VERSION 5.7 ;
BUSBITCHARS "[]" ;
DIVIDERCHAR "/" ;

PROPERTYDEFINITIONS
  LAYER LEF58_TYPE STRING ;
  LAYER LEF58_ENCLOSURE STRING ;
  LAYER LEF58_SPACING STRING ;
  LAYER LEF58_WIDTH STRING ;
END PROPERTYDEFINITIONS

UNITS
  TIME NANOSECONDS 1 ;
  CAPACITANCE PICOFARADS 1 ;
  RESISTANCE OHMS 1 ;
  DATABASE MICRONS 1000 ;
END UNITS
MANUFACTURINGGRID 0.005 ;
LAYER OverlapCheck
  TYPE OVERLAP ;
END OverlapCheck

LAYER WN
  TYPE MASTERSLICE ;
  PROPERTY LEF58_TYPE "TYPE NWELL ;" ;
  PROPERTY LEF58_SPACING "SPACING 2.8 ;" ;
  PROPERTY LEF58_WIDTH "WIDTH 0.86 ;" ;
END WN

LAYER ACTIVE
  TYPE MASTERSLICE ;
  PROPERTY LEF58_TYPE "TYPE DIFFUSION ;" ;
END ACTIVE

LAYER XP
  TYPE IMPLANT ;
  WIDTH 0.44 ;
  SPACING 0.44 ;
END XP

LAYER XN
  TYPE IMPLANT ;
  WIDTH 0.44 ;
  SPACING 0.44 ;
END XN

LAYER GC
  TYPE MASTERSLICE ;
END GC

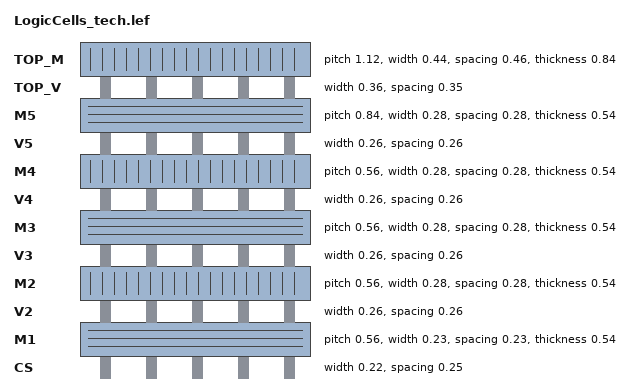
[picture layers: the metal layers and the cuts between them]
LAYER CS
  TYPE CUT ;
  SPACING 0.25 ;
  WIDTH 0.22 ;
  ENCLOSURE BELOW 0.1 0.1 ;
  ENCLOSURE ABOVE 0.06 0.005 ;
  ANTENNAMODEL OXIDE1 ;
END CS

LAYER M1
  TYPE ROUTING ;
  DIRECTION HORIZONTAL ;
  PITCH 0.56 0.56 ;
  WIDTH 0.23 ;
  OFFSET 0.28 ;
  AREA 0.202 ;
  SPACING 0.23 ;
  SPACING 0.6 RANGE 10 10000 ;
  SPACING 0.23 SAMENET ;
  RESISTANCE RPERSQ 0.08 ;
  CAPACITANCE CPERSQDIST 3.51e-05 ;
  HEIGHT 1.05 ;
  THICKNESS 0.54 ;
  ANTENNAMODEL OXIDE1 ;
    ANTENNASIDEAREARATIO 400 ;
    ANTENNADIFFSIDEAREARATIO PWL ( ( 0 400 ) ( 0.203 400 ) ( 0.203001 2281.2 ) ( 1.203 2681.2 ) ) ;
END M1

LAYER V2
  TYPE CUT ;
  SPACING 0.26 ;
  SPACING 0 LAYER CS ;
  WIDTH 0.26 ;
  ENCLOSURE BELOW 0.06 0.01 ;
  ENCLOSURE ABOVE 0.06 0.01 ;
  ANTENNAMODEL OXIDE1 ;
    ANTENNAAREARATIO 20 ;
    ANTENNADIFFAREARATIO PWL ( ( 0 20 ) ( 0.203 20 ) ( 0.203001 91.9161 ) ( 1.203 175.246 ) ) ;
END V2

LAYER M2
  TYPE ROUTING ;
  DIRECTION VERTICAL ;
  PITCH 0.56 0.56 ;
  WIDTH 0.28 ;
  OFFSET 0.28 ;
  AREA 0.202 ;
  SPACING 0.28 ;
  SPACING 0.6 RANGE 10 10000 ;
  SPACING 0.28 SAMENET ;
  RESISTANCE RPERSQ 0.08 ;
  CAPACITANCE CPERSQDIST 1.46e-05 ;
  HEIGHT 2.41 ;
  THICKNESS 0.54 ;
  ANTENNAMODEL OXIDE1 ;
    ANTENNASIDEAREARATIO 400 ;
    ANTENNADIFFSIDEAREARATIO PWL ( ( 0 400 ) ( 0.203 400 ) ( 0.203001 2281.2 ) ( 1.203 2681.2 ) ) ;
END M2

LAYER V3
  TYPE CUT ;
  SPACING 0.26 ;
  SPACING 0 SAMENET LAYER V2 STACK ;
  WIDTH 0.26 ;
  ENCLOSURE BELOW 0.06 0.01 ;
  ENCLOSURE ABOVE 0.06 0.01 ;
  ANTENNAMODEL OXIDE1 ;
    ANTENNAAREARATIO 20 ;
    ANTENNADIFFAREARATIO PWL ( ( 0 20 ) ( 0.203 20 ) ( 0.203001 91.9161 ) ( 1.203 175.246 ) ) ;
END V3

LAYER M3
  TYPE ROUTING ;
  DIRECTION HORIZONTAL ;
  PITCH 0.56 0.56 ;
  WIDTH 0.28 ;
  OFFSET 0.28 ;
  AREA 0.202 ;
  SPACING 0.28 ;
  SPACING 0.6 RANGE 10 10000 ;
  SPACING 0.28 SAMENET ;
  RESISTANCE RPERSQ 0.08 ;
  CAPACITANCE CPERSQDIST 9.24e-06 ;
  HEIGHT 3.77 ;
  THICKNESS 0.54 ;
  ANTENNAMODEL OXIDE1 ;
    ANTENNASIDEAREARATIO 400 ;
    ANTENNADIFFSIDEAREARATIO PWL ( ( 0 400 ) ( 0.203 400 ) ( 0.203001 2281.2 ) ( 1.203 2681.2 ) ) ;
END M3

LAYER V4
  TYPE CUT ;
  SPACING 0.26 ;
  SPACING 0 SAMENET LAYER V3 STACK ;
  WIDTH 0.26 ;
  ENCLOSURE BELOW 0.06 0.01 ;
  ENCLOSURE ABOVE 0.06 0.01 ;
  ANTENNAMODEL OXIDE1 ;
    ANTENNAAREARATIO 20 ;
    ANTENNADIFFAREARATIO PWL ( ( 0 20 ) ( 0.203 20 ) ( 0.203001 91.9161 ) ( 1.203 175.246 ) ) ;
END V4

LAYER M4
  TYPE ROUTING ;
  DIRECTION VERTICAL ;
  PITCH 0.56 0.56 ;
  WIDTH 0.28 ;
  OFFSET 0.28 ;
  AREA 0.202 ;
  SPACING 0.28 ;
  SPACING 0.6 RANGE 10 10000 ;
  SPACING 0.28 SAMENET ;
  RESISTANCE RPERSQ 0.08 ;
  CAPACITANCE CPERSQDIST 6.75e-06 ;
  HEIGHT 5.13 ;
  THICKNESS 0.54 ;
  ANTENNAMODEL OXIDE1 ;
    ANTENNASIDEAREARATIO 400 ;
    ANTENNADIFFSIDEAREARATIO PWL ( ( 0 400 ) ( 0.203 400 ) ( 0.203001 2281.2 ) ( 1.203 2681.2 ) ) ;
END M4

LAYER V5
  TYPE CUT ;
  SPACING 0.26 ;
  SPACING 0 SAMENET LAYER V4 STACK ;
  WIDTH 0.26 ;
  ENCLOSURE BELOW 0.06 0.01 ;
  ENCLOSURE ABOVE 0.06 0.01 ;
  ANTENNAMODEL OXIDE1 ;
    ANTENNAAREARATIO 20 ;
    ANTENNADIFFAREARATIO PWL ( ( 0 20 ) ( 0.203 20 ) ( 0.203001 91.9161 ) ( 1.203 175.246 ) ) ;
END V5

LAYER M5
  TYPE ROUTING ;
  DIRECTION HORIZONTAL ;
  PITCH 0.84 0.84 ;
  WIDTH 0.28 ;
  OFFSET 0.42 ;
  AREA 0.202 ;
  SPACING 0.28 ;
  SPACING 0.6 RANGE 10 10000 ;
  SPACING 0.28 SAMENET ;
  RESISTANCE RPERSQ 0.08 ;
  CAPACITANCE CPERSQDIST 5.32e-06 ;
  HEIGHT 6.49 ;
  THICKNESS 0.54 ;
  ANTENNAMODEL OXIDE1 ;
    ANTENNASIDEAREARATIO 400 ;
    ANTENNADIFFSIDEAREARATIO PWL ( ( 0 400 ) ( 0.203 400 ) ( 0.203001 2281.2 ) ( 1.203 2681.2 ) ) ;
END M5

LAYER TOP_V
  TYPE CUT ;
  SPACING 0.35 ;
  SPACING 0 SAMENET LAYER V5 STACK ;
  WIDTH 0.36 ;
  ENCLOSURE BELOW 0.06 0.01 ;
  ENCLOSURE ABOVE 0.09 0.09 ;
  ANTENNAMODEL OXIDE1 ;
    ANTENNAAREARATIO 20 ;
    ANTENNADIFFAREARATIO PWL ( ( 0 20 ) ( 0.203 20 ) ( 0.203001 91.9161 ) ( 1.203 175.246 ) ) ;
END TOP_V

LAYER TOP_M
  TYPE ROUTING ;
  DIRECTION VERTICAL ;
  PITCH 1.12 1.12 ;
  WIDTH 0.44 ;
  OFFSET 0.56 ;
  AREA 0.562 ;
  SPACING 0.46 ;
  SPACING 0.6 RANGE 10 10000 ;
  SPACING 0.46 SAMENET ;
  RESISTANCE RPERSQ 0.04 ;
  CAPACITANCE CPERSQDIST 4.389e-06 ;
  HEIGHT 7.83 ;
  THICKNESS 0.84 ;
  ANTENNAMODEL OXIDE1 ;
    ANTENNASIDEAREARATIO 400 ;
    ANTENNADIFFSIDEAREARATIO PWL ( ( 0 400 ) ( 0.203 400 ) ( 0.203001 31624 ) ( 1.203 39624 ) ) ;
END TOP_M

VIARULE ML_M5_LD GENERATE
  LAYER M5 ;
    ENCLOSURE 0.1 0.1 ;
  LAYER TOP_M ;
    ENCLOSURE 0.1 0.1 ;
  LAYER TOP_V ;
    RECT -0.18 -0.18 0.18 0.18 ;
    SPACING 0.71 BY 0.71 ;
END ML_M5_LD

VIARULE M5_M4_LD GENERATE
  LAYER M4 ;
    ENCLOSURE 0.1 0.1 ;
  LAYER M5 ;
    ENCLOSURE 0.1 0.1 ;
  LAYER V5 ;
    RECT -0.13 -0.13 0.13 0.13 ;
    SPACING 0.52 BY 0.52 ;
END M5_M4_LD

VIARULE M4_M3_LD GENERATE
  LAYER M3 ;
    ENCLOSURE 0.1 0.1 ;
  LAYER M4 ;
    ENCLOSURE 0.1 0.1 ;
  LAYER V4 ;
    RECT -0.13 -0.13 0.13 0.13 ;
    SPACING 0.52 BY 0.52 ;
END M4_M3_LD

VIARULE M3_M2_LD GENERATE
  LAYER M2 ;
    ENCLOSURE 0.1 0.1 ;
  LAYER M3 ;
    ENCLOSURE 0.1 0.1 ;
  LAYER V3 ;
    RECT -0.13 -0.13 0.13 0.13 ;
    SPACING 0.52 BY 0.52 ;
END M3_M2_LD

VIARULE M2_M1_LD GENERATE
  LAYER M1 ;
    ENCLOSURE 0.1 0.1 ;
  LAYER M2 ;
    ENCLOSURE 0.1 0.1 ;
  LAYER V2 ;
    RECT -0.13 -0.13 0.13 0.13 ;
    SPACING 0.52 BY 0.52 ;
END M2_M1_LD

VIARULE ML_M5_S GENERATE DEFAULT
  LAYER M5 ;
    ENCLOSURE 0.01 0.01 ;
  LAYER TOP_M ;
    ENCLOSURE 0.09 0.09 ;
  LAYER TOP_V ;
    RECT -0.18 -0.18 0.18 0.18 ;
    SPACING 0.71 BY 0.71 ;
END ML_M5_S

VIARULE M5_M4_S GENERATE DEFAULT
  LAYER M4 ;
    ENCLOSURE 0.01 0.01 ;
  LAYER M5 ;
    ENCLOSURE 0.01 0.01 ;
  LAYER V5 ;
    RECT -0.13 -0.13 0.13 0.13 ;
    SPACING 0.52 BY 0.52 ;
END M5_M4_S

VIARULE M4_M3_S GENERATE DEFAULT
  LAYER M3 ;
    ENCLOSURE 0.01 0.01 ;
  LAYER M4 ;
    ENCLOSURE 0.01 0.01 ;
  LAYER V4 ;
    RECT -0.13 -0.13 0.13 0.13 ;
    SPACING 0.52 BY 0.52 ;
END M4_M3_S

VIARULE M3_M2_S GENERATE DEFAULT
  LAYER M2 ;
    ENCLOSURE 0.01 0.01 ;
  LAYER M3 ;
    ENCLOSURE 0.01 0.01 ;
  LAYER V3 ;
    RECT -0.13 -0.13 0.13 0.13 ;
    SPACING 0.52 BY 0.52 ;
END M3_M2_S

VIARULE M2_M1_S GENERATE DEFAULT
  LAYER M1 ;
    ENCLOSURE 0.01 0.01 ;
  LAYER M2 ;
    ENCLOSURE 0.01 0.01 ;
  LAYER V2 ;
    RECT -0.13 -0.13 0.13 0.13 ;
    SPACING 0.52 BY 0.52 ;
END M2_M1_S

VIARULE ML_M5 GENERATE
  LAYER M5 ;
    ENCLOSURE 0.06 0.06 ;
  LAYER TOP_M ;
    ENCLOSURE 0.09 0.09 ;
  LAYER TOP_V ;
    RECT -0.18 -0.18 0.18 0.18 ;
    SPACING 0.71 BY 0.71 ;
END ML_M5

VIARULE M5_M4 GENERATE
  LAYER M4 ;
    ENCLOSURE 0.06 0.06 ;
  LAYER M5 ;
    ENCLOSURE 0.06 0.06 ;
  LAYER V5 ;
    RECT -0.13 -0.13 0.13 0.13 ;
    SPACING 0.52 BY 0.52 ;
END M5_M4

VIARULE M4_M3 GENERATE
  LAYER M3 ;
    ENCLOSURE 0.06 0.06 ;
  LAYER M4 ;
    ENCLOSURE 0.06 0.06 ;
  LAYER V4 ;
    RECT -0.13 -0.13 0.13 0.13 ;
    SPACING 0.52 BY 0.52 ;
END M4_M3

VIARULE M3_M2 GENERATE
  LAYER M2 ;
    ENCLOSURE 0.06 0.06 ;
  LAYER M3 ;
    ENCLOSURE 0.06 0.06 ;
  LAYER V3 ;
    RECT -0.13 -0.13 0.13 0.13 ;
    SPACING 0.52 BY 0.52 ;
END M3_M2

VIARULE M2_M1 GENERATE
  LAYER M1 ;
    ENCLOSURE 0.06 0.06 ;
  LAYER M2 ;
    ENCLOSURE 0.06 0.06 ;
  LAYER V2 ;
    RECT -0.13 -0.13 0.13 0.13 ;
    SPACING 0.52 BY 0.52 ;
END M2_M1

VIARULE M1_PO_4X GENERATE
  LAYER GC ;
    ENCLOSURE 0.1 0.1 ;
  LAYER M1 ;
    ENCLOSURE 0.06 0.06 ;
  LAYER CS ;
    RECT -0.11 -0.11 0.11 0.11 ;
    SPACING 0.5 BY 0.5 ;
END M1_PO_4X

VIARULE M1_PO GENERATE
  LAYER GC ;
    ENCLOSURE 0.1 0.1 ;
  LAYER M1 ;
    ENCLOSURE 0.06 0.06 ;
  LAYER CS ;
    RECT -0.11 -0.11 0.11 0.11 ;
    SPACING 0.47 BY 0.47 ;
END M1_PO

VIARULE PTAP_4X_LG GENERATE
  LAYER ACTIVE ;
    ENCLOSURE 0.1 0.1 ;
  LAYER M1 ;
    ENCLOSURE 0.06 0.06 ;
  LAYER CS ;
    RECT -0.11 -0.11 0.11 0.11 ;
    SPACING 0.5 BY 0.5 ;
END PTAP_4X_LG

VIARULE PTAP_4X GENERATE
  LAYER ACTIVE ;
    ENCLOSURE 0.1 0.1 ;
  LAYER M1 ;
    ENCLOSURE 0.06 0.06 ;
  LAYER CS ;
    RECT -0.11 -0.11 0.11 0.11 ;
    SPACING 0.5 BY 0.5 ;
END PTAP_4X

VIARULE PTAP_LG GENERATE
  LAYER ACTIVE ;
    ENCLOSURE 0.1 0.1 ;
  LAYER M1 ;
    ENCLOSURE 0.06 0.06 ;
  LAYER CS ;
    RECT -0.11 -0.11 0.11 0.11 ;
    SPACING 0.47 BY 0.47 ;
END PTAP_LG

VIARULE PTAP GENERATE
  LAYER ACTIVE ;
    ENCLOSURE 0.1 0.1 ;
  LAYER M1 ;
    ENCLOSURE 0.06 0.06 ;
  LAYER CS ;
    RECT -0.11 -0.11 0.11 0.11 ;
    SPACING 0.47 BY 0.47 ;
END PTAP

VIARULE NTAP_4X_LG GENERATE
  LAYER ACTIVE ;
    ENCLOSURE 0.1 0.1 ;
  LAYER M1 ;
    ENCLOSURE 0.06 0.06 ;
  LAYER CS ;
    RECT -0.11 -0.11 0.11 0.11 ;
    SPACING 0.5 BY 0.5 ;
END NTAP_4X_LG

VIARULE NTAP_4X GENERATE
  LAYER ACTIVE ;
    ENCLOSURE 0.1 0.1 ;
  LAYER M1 ;
    ENCLOSURE 0.06 0.06 ;
  LAYER CS ;
    RECT -0.11 -0.11 0.11 0.11 ;
    SPACING 0.5 BY 0.5 ;
END NTAP_4X

VIARULE NTAP_LG GENERATE
  LAYER ACTIVE ;
    ENCLOSURE 0.1 0.1 ;
  LAYER M1 ;
    ENCLOSURE 0.06 0.06 ;
  LAYER CS ;
    RECT -0.11 -0.11 0.11 0.11 ;
    SPACING 0.47 BY 0.47 ;
END NTAP_LG

VIARULE NTAP GENERATE
  LAYER ACTIVE ;
    ENCLOSURE 0.1 0.1 ;
  LAYER M1 ;
    ENCLOSURE 0.06 0.06 ;
  LAYER CS ;
    RECT -0.11 -0.11 0.11 0.11 ;
    SPACING 0.47 BY 0.47 ;
END NTAP

VIARULE M1_WN GENERATE
  LAYER ACTIVE ;
    ENCLOSURE 0.1 0.1 ;
  LAYER M1 ;
    ENCLOSURE 0.06 0.06 ;
  LAYER CS ;
    RECT -0.11 -0.11 0.11 0.11 ;
    SPACING 0.47 BY 0.47 ;
END M1_WN

END LIBRARY
